VERSION 5.8 ;
BUSBITCHARS "[]" ;
DIVIDERCHAR "/" ;
UNITS
    DATABASE MICRONS 1000 ;
END UNITS

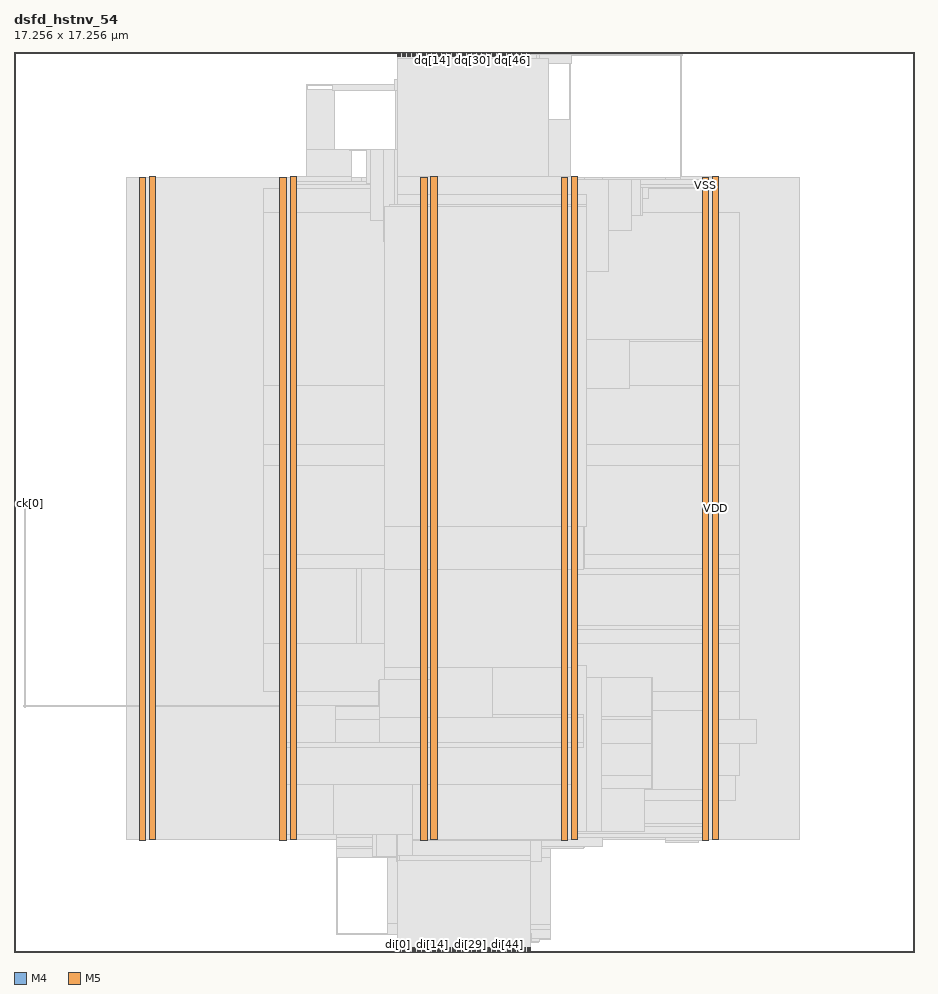
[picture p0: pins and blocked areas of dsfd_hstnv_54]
MACRO dsfd_hstnv_54
  FOREIGN dsfd_hstnv_54 0 0 ;
  CLASS BLOCK ;
  SIZE 17.256 BY 17.256 ;
  PIN ck[0]
    DIRECTION INPUT ;
    USE SIGNAL ;
    PORT
      LAYER M4 ;
        RECT  0 8.592 0.084 8.616 ;
    END
    PORT
      LAYER M4 ;
        RECT  0.06 8.592 0.227 8.616 ;
    END
  END ck[0]
  PIN di[0]
    DIRECTION INPUT ;
    USE SIGNAL ;
    PORT
      LAYER M5 ;
        RECT  7.344 0 7.368 0.084 ;
    END
  END di[0]
  PIN di[10]
    DIRECTION INPUT ;
    USE SIGNAL ;
    PORT
      LAYER M5 ;
        RECT  7.824 0 7.848 0.084 ;
    END
  END di[10]
  PIN di[11]
    DIRECTION INPUT ;
    USE SIGNAL ;
    PORT
      LAYER M5 ;
        RECT  7.872 0 7.896 0.084 ;
    END
  END di[11]
  PIN di[12]
    DIRECTION INPUT ;
    USE SIGNAL ;
    PORT
      LAYER M5 ;
        RECT  7.92 0 7.944 0.084 ;
    END
  END di[12]
  PIN di[13]
    DIRECTION INPUT ;
    USE SIGNAL ;
    PORT
      LAYER M5 ;
        RECT  7.968 0 7.992 0.084 ;
    END
  END di[13]
  PIN di[14]
    DIRECTION INPUT ;
    USE SIGNAL ;
    PORT
      LAYER M5 ;
        RECT  8.016 0 8.04 0.084 ;
    END
  END di[14]
  PIN di[15]
    DIRECTION INPUT ;
    USE SIGNAL ;
    PORT
      LAYER M5 ;
        RECT  8.064 0 8.088 0.084 ;
    END
  END di[15]
  PIN di[16]
    DIRECTION INPUT ;
    USE SIGNAL ;
    PORT
      LAYER M5 ;
        RECT  8.112 0 8.136 0.084 ;
    END
  END di[16]
  PIN di[17]
    DIRECTION INPUT ;
    USE SIGNAL ;
    PORT
      LAYER M5 ;
        RECT  8.16 0 8.184 0.084 ;
    END
  END di[17]
  PIN di[18]
    DIRECTION INPUT ;
    USE SIGNAL ;
    PORT
      LAYER M5 ;
        RECT  8.208 0 8.232 0.084 ;
    END
  END di[18]
  PIN di[19]
    DIRECTION INPUT ;
    USE SIGNAL ;
    PORT
      LAYER M5 ;
        RECT  8.256 0 8.28 0.084 ;
    END
  END di[19]
  PIN di[1]
    DIRECTION INPUT ;
    USE SIGNAL ;
    PORT
      LAYER M5 ;
        RECT  7.392 0 7.416 0.084 ;
    END
  END di[1]
  PIN di[20]
    DIRECTION INPUT ;
    USE SIGNAL ;
    PORT
      LAYER M5 ;
        RECT  8.304 0 8.328 0.084 ;
    END
  END di[20]
  PIN di[21]
    DIRECTION INPUT ;
    USE SIGNAL ;
    PORT
      LAYER M5 ;
        RECT  8.352 0 8.376 0.084 ;
    END
  END di[21]
  PIN di[22]
    DIRECTION INPUT ;
    USE SIGNAL ;
    PORT
      LAYER M5 ;
        RECT  8.4 0 8.424 0.084 ;
    END
  END di[22]
  PIN di[23]
    DIRECTION INPUT ;
    USE SIGNAL ;
    PORT
      LAYER M5 ;
        RECT  8.448 0 8.472 0.084 ;
    END
  END di[23]
  PIN di[24]
    DIRECTION INPUT ;
    USE SIGNAL ;
    PORT
      LAYER M5 ;
        RECT  8.496 0 8.52 0.084 ;
    END
  END di[24]
  PIN di[25]
    DIRECTION INPUT ;
    USE SIGNAL ;
    PORT
      LAYER M5 ;
        RECT  8.544 0 8.568 0.084 ;
    END
  END di[25]
  PIN di[26]
    DIRECTION INPUT ;
    USE SIGNAL ;
    PORT
      LAYER M5 ;
        RECT  8.592 0 8.616 0.084 ;
    END
  END di[26]
  PIN di[27]
    DIRECTION INPUT ;
    USE SIGNAL ;
    PORT
      LAYER M5 ;
        RECT  8.64 0 8.664 0.084 ;
    END
  END di[27]
  PIN di[28]
    DIRECTION INPUT ;
    USE SIGNAL ;
    PORT
      LAYER M5 ;
        RECT  8.688 0 8.712 0.084 ;
    END
  END di[28]
  PIN di[29]
    DIRECTION INPUT ;
    USE SIGNAL ;
    PORT
      LAYER M5 ;
        RECT  8.736 0 8.76 0.084 ;
    END
  END di[29]
  PIN di[2]
    DIRECTION INPUT ;
    USE SIGNAL ;
    PORT
      LAYER M5 ;
        RECT  7.44 0 7.464 0.084 ;
    END
  END di[2]
  PIN di[30]
    DIRECTION INPUT ;
    USE SIGNAL ;
    PORT
      LAYER M5 ;
        RECT  8.784 0 8.808 0.084 ;
    END
  END di[30]
  PIN di[31]
    DIRECTION INPUT ;
    USE SIGNAL ;
    PORT
      LAYER M5 ;
        RECT  8.832 0 8.856 0.084 ;
    END
  END di[31]
  PIN di[32]
    DIRECTION INPUT ;
    USE SIGNAL ;
    PORT
      LAYER M5 ;
        RECT  8.88 0 8.904 0.084 ;
    END
  END di[32]
  PIN di[33]
    DIRECTION INPUT ;
    USE SIGNAL ;
    PORT
      LAYER M5 ;
        RECT  8.928 0 8.952 0.084 ;
    END
  END di[33]
  PIN di[34]
    DIRECTION INPUT ;
    USE SIGNAL ;
    PORT
      LAYER M5 ;
        RECT  8.976 0 9 0.084 ;
    END
  END di[34]
  PIN di[35]
    DIRECTION INPUT ;
    USE SIGNAL ;
    PORT
      LAYER M5 ;
        RECT  9.024 0 9.048 0.084 ;
    END
  END di[35]
  PIN di[36]
    DIRECTION INPUT ;
    USE SIGNAL ;
    PORT
      LAYER M5 ;
        RECT  9.072 0 9.096 0.084 ;
    END
  END di[36]
  PIN di[37]
    DIRECTION INPUT ;
    USE SIGNAL ;
    PORT
      LAYER M5 ;
        RECT  9.12 0 9.144 0.084 ;
    END
  END di[37]
  PIN di[38]
    DIRECTION INPUT ;
    USE SIGNAL ;
    PORT
      LAYER M5 ;
        RECT  9.168 0 9.192 0.084 ;
    END
  END di[38]
  PIN di[39]
    DIRECTION INPUT ;
    USE SIGNAL ;
    PORT
      LAYER M5 ;
        RECT  9.216 0 9.24 0.084 ;
    END
  END di[39]
  PIN di[3]
    DIRECTION INPUT ;
    USE SIGNAL ;
    PORT
      LAYER M5 ;
        RECT  7.488 0 7.512 0.084 ;
    END
  END di[3]
  PIN di[40]
    DIRECTION INPUT ;
    USE SIGNAL ;
    PORT
      LAYER M5 ;
        RECT  9.264 0 9.288 0.084 ;
    END
  END di[40]
  PIN di[41]
    DIRECTION INPUT ;
    USE SIGNAL ;
    PORT
      LAYER M5 ;
        RECT  9.312 0 9.336 0.084 ;
    END
  END di[41]
  PIN di[42]
    DIRECTION INPUT ;
    USE SIGNAL ;
    PORT
      LAYER M5 ;
        RECT  9.36 0 9.384 0.084 ;
    END
  END di[42]
  PIN di[43]
    DIRECTION INPUT ;
    USE SIGNAL ;
    PORT
      LAYER M5 ;
        RECT  9.408 0 9.432 0.084 ;
    END
  END di[43]
  PIN di[44]
    DIRECTION INPUT ;
    USE SIGNAL ;
    PORT
      LAYER M5 ;
        RECT  9.456 0 9.48 0.084 ;
    END
  END di[44]
  PIN di[45]
    DIRECTION INPUT ;
    USE SIGNAL ;
    PORT
      LAYER M5 ;
        RECT  9.504 0 9.528 0.084 ;
    END
  END di[45]
  PIN di[46]
    DIRECTION INPUT ;
    USE SIGNAL ;
    PORT
      LAYER M5 ;
        RECT  9.552 0 9.576 0.084 ;
    END
  END di[46]
  PIN di[47]
    DIRECTION INPUT ;
    USE SIGNAL ;
    PORT
      LAYER M5 ;
        RECT  9.6 0 9.624 0.084 ;
    END
  END di[47]
  PIN di[48]
    DIRECTION INPUT ;
    USE SIGNAL ;
    PORT
      LAYER M5 ;
        RECT  9.648 0 9.672 0.084 ;
    END
  END di[48]
  PIN di[49]
    DIRECTION INPUT ;
    USE SIGNAL ;
    PORT
      LAYER M5 ;
        RECT  9.696 0 9.72 0.084 ;
    END
  END di[49]
  PIN di[4]
    DIRECTION INPUT ;
    USE SIGNAL ;
    PORT
      LAYER M5 ;
        RECT  7.536 0 7.56 0.084 ;
    END
  END di[4]
  PIN di[50]
    DIRECTION INPUT ;
    USE SIGNAL ;
    PORT
      LAYER M5 ;
        RECT  9.744 0 9.768 0.084 ;
    END
  END di[50]
  PIN di[51]
    DIRECTION INPUT ;
    USE SIGNAL ;
    PORT
      LAYER M5 ;
        RECT  9.792 0 9.816 0.084 ;
    END
  END di[51]
  PIN di[52]
    DIRECTION INPUT ;
    USE SIGNAL ;
    PORT
      LAYER M5 ;
        RECT  9.84 0 9.864 0.084 ;
    END
  END di[52]
  PIN di[53]
    DIRECTION INPUT ;
    USE SIGNAL ;
    PORT
      LAYER M5 ;
        RECT  9.888 0 9.912 0.084 ;
    END
  END di[53]
  PIN di[5]
    DIRECTION INPUT ;
    USE SIGNAL ;
    PORT
      LAYER M5 ;
        RECT  7.584 0 7.608 0.084 ;
    END
  END di[5]
  PIN di[6]
    DIRECTION INPUT ;
    USE SIGNAL ;
    PORT
      LAYER M5 ;
        RECT  7.632 0 7.656 0.084 ;
    END
  END di[6]
  PIN di[7]
    DIRECTION INPUT ;
    USE SIGNAL ;
    PORT
      LAYER M5 ;
        RECT  7.68 0 7.704 0.084 ;
    END
  END di[7]
  PIN di[8]
    DIRECTION INPUT ;
    USE SIGNAL ;
    PORT
      LAYER M5 ;
        RECT  7.728 0 7.752 0.084 ;
    END
  END di[8]
  PIN di[9]
    DIRECTION INPUT ;
    USE SIGNAL ;
    PORT
      LAYER M5 ;
        RECT  7.776 0 7.8 0.084 ;
    END
  END di[9]
  PIN dq[0]
    DIRECTION OUTPUT ;
    USE SIGNAL ;
    PORT
      LAYER M5 ;
        RECT  7.344 17.172 7.368 17.256 ;
    END
  END dq[0]
  PIN dq[10]
    DIRECTION OUTPUT ;
    USE SIGNAL ;
    PORT
      LAYER M5 ;
        RECT  7.824 17.172 7.848 17.256 ;
    END
  END dq[10]
  PIN dq[11]
    DIRECTION OUTPUT ;
    USE SIGNAL ;
    PORT
      LAYER M5 ;
        RECT  7.872 17.172 7.896 17.256 ;
    END
  END dq[11]
  PIN dq[12]
    DIRECTION OUTPUT ;
    USE SIGNAL ;
    PORT
      LAYER M5 ;
        RECT  7.92 17.172 7.944 17.256 ;
    END
  END dq[12]
  PIN dq[13]
    DIRECTION OUTPUT ;
    USE SIGNAL ;
    PORT
      LAYER M5 ;
        RECT  7.968 17.172 7.992 17.256 ;
    END
  END dq[13]
  PIN dq[14]
    DIRECTION OUTPUT ;
    USE SIGNAL ;
    PORT
      LAYER M5 ;
        RECT  8.016 17.172 8.04 17.256 ;
    END
  END dq[14]
  PIN dq[15]
    DIRECTION OUTPUT ;
    USE SIGNAL ;
    PORT
      LAYER M5 ;
        RECT  8.064 17.172 8.088 17.256 ;
    END
  END dq[15]
  PIN dq[16]
    DIRECTION OUTPUT ;
    USE SIGNAL ;
    PORT
      LAYER M5 ;
        RECT  8.112 17.172 8.136 17.256 ;
    END
  END dq[16]
  PIN dq[17]
    DIRECTION OUTPUT ;
    USE SIGNAL ;
    PORT
      LAYER M5 ;
        RECT  8.16 17.172 8.184 17.256 ;
    END
  END dq[17]
  PIN dq[18]
    DIRECTION OUTPUT ;
    USE SIGNAL ;
    PORT
      LAYER M5 ;
        RECT  8.208 17.172 8.232 17.256 ;
    END
  END dq[18]
  PIN dq[19]
    DIRECTION OUTPUT ;
    USE SIGNAL ;
    PORT
      LAYER M5 ;
        RECT  8.256 17.172 8.28 17.256 ;
    END
  END dq[19]
  PIN dq[1]
    DIRECTION OUTPUT ;
    USE SIGNAL ;
    PORT
      LAYER M5 ;
        RECT  7.392 17.172 7.416 17.256 ;
    END
  END dq[1]
  PIN dq[20]
    DIRECTION OUTPUT ;
    USE SIGNAL ;
    PORT
      LAYER M5 ;
        RECT  8.304 17.172 8.328 17.256 ;
    END
  END dq[20]
  PIN dq[21]
    DIRECTION OUTPUT ;
    USE SIGNAL ;
    PORT
      LAYER M5 ;
        RECT  8.352 17.172 8.376 17.256 ;
    END
  END dq[21]
  PIN dq[22]
    DIRECTION OUTPUT ;
    USE SIGNAL ;
    PORT
      LAYER M5 ;
        RECT  8.4 17.172 8.424 17.256 ;
    END
  END dq[22]
  PIN dq[23]
    DIRECTION OUTPUT ;
    USE SIGNAL ;
    PORT
      LAYER M5 ;
        RECT  8.448 17.172 8.472 17.256 ;
    END
  END dq[23]
  PIN dq[24]
    DIRECTION OUTPUT ;
    USE SIGNAL ;
    PORT
      LAYER M5 ;
        RECT  8.496 17.172 8.52 17.256 ;
    END
  END dq[24]
  PIN dq[25]
    DIRECTION OUTPUT ;
    USE SIGNAL ;
    PORT
      LAYER M5 ;
        RECT  8.544 17.172 8.568 17.256 ;
    END
  END dq[25]
  PIN dq[26]
    DIRECTION OUTPUT ;
    USE SIGNAL ;
    PORT
      LAYER M5 ;
        RECT  8.592 17.172 8.616 17.256 ;
    END
  END dq[26]
  PIN dq[27]
    DIRECTION OUTPUT ;
    USE SIGNAL ;
    PORT
      LAYER M5 ;
        RECT  8.64 17.172 8.664 17.256 ;
    END
  END dq[27]
  PIN dq[28]
    DIRECTION OUTPUT ;
    USE SIGNAL ;
    PORT
      LAYER M5 ;
        RECT  8.688 17.172 8.712 17.256 ;
    END
  END dq[28]
  PIN dq[29]
    DIRECTION OUTPUT ;
    USE SIGNAL ;
    PORT
      LAYER M5 ;
        RECT  8.736 17.172 8.76 17.256 ;
    END
  END dq[29]
  PIN dq[2]
    DIRECTION OUTPUT ;
    USE SIGNAL ;
    PORT
      LAYER M5 ;
        RECT  7.44 17.172 7.464 17.256 ;
    END
  END dq[2]
  PIN dq[30]
    DIRECTION OUTPUT ;
    USE SIGNAL ;
    PORT
      LAYER M5 ;
        RECT  8.784 17.172 8.808 17.256 ;
    END
  END dq[30]
  PIN dq[31]
    DIRECTION OUTPUT ;
    USE SIGNAL ;
    PORT
      LAYER M5 ;
        RECT  8.832 17.172 8.856 17.256 ;
    END
  END dq[31]
  PIN dq[32]
    DIRECTION OUTPUT ;
    USE SIGNAL ;
    PORT
      LAYER M5 ;
        RECT  8.88 17.172 8.904 17.256 ;
    END
  END dq[32]
  PIN dq[33]
    DIRECTION OUTPUT ;
    USE SIGNAL ;
    PORT
      LAYER M5 ;
        RECT  8.928 17.172 8.952 17.256 ;
    END
  END dq[33]
  PIN dq[34]
    DIRECTION OUTPUT ;
    USE SIGNAL ;
    PORT
      LAYER M5 ;
        RECT  8.976 17.172 9 17.256 ;
    END
  END dq[34]
  PIN dq[35]
    DIRECTION OUTPUT ;
    USE SIGNAL ;
    PORT
      LAYER M5 ;
        RECT  9.024 17.172 9.048 17.256 ;
    END
  END dq[35]
  PIN dq[36]
    DIRECTION OUTPUT ;
    USE SIGNAL ;
    PORT
      LAYER M5 ;
        RECT  9.072 17.172 9.096 17.256 ;
    END
  END dq[36]
  PIN dq[37]
    DIRECTION OUTPUT ;
    USE SIGNAL ;
    PORT
      LAYER M5 ;
        RECT  9.12 17.172 9.144 17.256 ;
    END
  END dq[37]
  PIN dq[38]
    DIRECTION OUTPUT ;
    USE SIGNAL ;
    PORT
      LAYER M5 ;
        RECT  9.168 17.172 9.192 17.256 ;
    END
  END dq[38]
  PIN dq[39]
    DIRECTION OUTPUT ;
    USE SIGNAL ;
    PORT
      LAYER M5 ;
        RECT  9.216 17.172 9.24 17.256 ;
    END
  END dq[39]
  PIN dq[3]
    DIRECTION OUTPUT ;
    USE SIGNAL ;
    PORT
      LAYER M5 ;
        RECT  7.488 17.172 7.512 17.256 ;
    END
  END dq[3]
  PIN dq[40]
    DIRECTION OUTPUT ;
    USE SIGNAL ;
    PORT
      LAYER M5 ;
        RECT  9.264 17.172 9.288 17.256 ;
    END
  END dq[40]
  PIN dq[41]
    DIRECTION OUTPUT ;
    USE SIGNAL ;
    PORT
      LAYER M5 ;
        RECT  9.312 17.172 9.336 17.256 ;
    END
  END dq[41]
  PIN dq[42]
    DIRECTION OUTPUT ;
    USE SIGNAL ;
    PORT
      LAYER M5 ;
        RECT  9.36 17.172 9.384 17.256 ;
    END
  END dq[42]
  PIN dq[43]
    DIRECTION OUTPUT ;
    USE SIGNAL ;
    PORT
      LAYER M5 ;
        RECT  9.408 17.172 9.432 17.256 ;
    END
  END dq[43]
  PIN dq[44]
    DIRECTION OUTPUT ;
    USE SIGNAL ;
    PORT
      LAYER M5 ;
        RECT  9.456 17.172 9.48 17.256 ;
    END
  END dq[44]
  PIN dq[45]
    DIRECTION OUTPUT ;
    USE SIGNAL ;
    PORT
      LAYER M5 ;
        RECT  9.504 17.172 9.528 17.256 ;
    END
  END dq[45]
  PIN dq[46]
    DIRECTION OUTPUT ;
    USE SIGNAL ;
    PORT
      LAYER M5 ;
        RECT  9.552 17.172 9.576 17.256 ;
    END
  END dq[46]
  PIN dq[47]
    DIRECTION OUTPUT ;
    USE SIGNAL ;
    PORT
      LAYER M5 ;
        RECT  9.6 17.172 9.624 17.256 ;
    END
  END dq[47]
  PIN dq[48]
    DIRECTION OUTPUT ;
    USE SIGNAL ;
    PORT
      LAYER M5 ;
        RECT  9.648 17.172 9.672 17.256 ;
    END
  END dq[48]
  PIN dq[49]
    DIRECTION OUTPUT ;
    USE SIGNAL ;
    PORT
      LAYER M5 ;
        RECT  9.696 17.172 9.72 17.256 ;
    END
  END dq[49]
  PIN dq[4]
    DIRECTION OUTPUT ;
    USE SIGNAL ;
    PORT
      LAYER M5 ;
        RECT  7.536 17.172 7.56 17.256 ;
    END
  END dq[4]
  PIN dq[50]
    DIRECTION OUTPUT ;
    USE SIGNAL ;
    PORT
      LAYER M5 ;
        RECT  9.744 17.172 9.768 17.256 ;
    END
  END dq[50]
  PIN dq[51]
    DIRECTION OUTPUT ;
    USE SIGNAL ;
    PORT
      LAYER M5 ;
        RECT  9.792 17.172 9.816 17.256 ;
    END
  END dq[51]
  PIN dq[52]
    DIRECTION OUTPUT ;
    USE SIGNAL ;
    PORT
      LAYER M5 ;
        RECT  9.84 17.172 9.864 17.256 ;
    END
  END dq[52]
  PIN dq[53]
    DIRECTION OUTPUT ;
    USE SIGNAL ;
    PORT
      LAYER M5 ;
        RECT  9.888 17.172 9.912 17.256 ;
    END
  END dq[53]
  PIN dq[5]
    DIRECTION OUTPUT ;
    USE SIGNAL ;
    PORT
      LAYER M5 ;
        RECT  7.584 17.172 7.608 17.256 ;
    END
  END dq[5]
  PIN dq[6]
    DIRECTION OUTPUT ;
    USE SIGNAL ;
    PORT
      LAYER M5 ;
        RECT  7.632 17.172 7.656 17.256 ;
    END
  END dq[6]
  PIN dq[7]
    DIRECTION OUTPUT ;
    USE SIGNAL ;
    PORT
      LAYER M5 ;
        RECT  7.68 17.172 7.704 17.256 ;
    END
  END dq[7]
  PIN dq[8]
    DIRECTION OUTPUT ;
    USE SIGNAL ;
    PORT
      LAYER M5 ;
        RECT  7.728 17.172 7.752 17.256 ;
    END
  END dq[8]
  PIN dq[9]
    DIRECTION OUTPUT ;
    USE SIGNAL ;
    PORT
      LAYER M5 ;
        RECT  7.776 17.172 7.8 17.256 ;
    END
  END dq[9]
  PIN VDD
    DIRECTION INOUT ;
    USE POWER ;
    PORT
      LAYER M5 ;
        RECT  13.392 2.151 13.512 14.873 ;
        RECT  10.692 2.151 10.812 14.873 ;
        RECT  7.992 2.151 8.112 14.873 ;
        RECT  5.292 2.151 5.412 14.873 ;
        RECT  2.592 2.151 2.712 14.873 ;
    END
  END VDD
  PIN VSS
    DIRECTION INOUT ;
    USE GROUND ;
    PORT
      LAYER M5 ;
        RECT  13.2 2.137 13.32 14.859 ;
        RECT  10.5 2.137 10.62 14.859 ;
        RECT  7.8 2.137 7.92 14.859 ;
        RECT  5.1 2.137 5.22 14.859 ;
        RECT  2.4 2.137 2.52 14.859 ;
    END
  END VSS
  # OT_OBS_CLOSED layer=M5 d_um=1.536 added=4
  OBS
    LAYER RVTN ;
     RECT  2.16 2.16 15.066 2.295 ;
     RECT  2.16 2.565 15.066 2.835 ;
     RECT  2.16 3.105 15.066 3.375 ;
     RECT  2.16 3.645 15.066 3.915 ;
     RECT  2.16 4.185 15.066 4.455 ;
     RECT  2.16 4.725 15.066 4.995 ;
     RECT  2.16 5.265 15.066 5.535 ;
     RECT  2.16 5.805 15.066 6.075 ;
     RECT  2.16 6.345 15.066 6.615 ;
     RECT  2.16 6.885 15.066 7.155 ;
     RECT  2.16 7.425 15.066 7.695 ;
     RECT  2.16 7.965 15.066 8.235 ;
     RECT  2.16 8.505 15.066 8.775 ;
     RECT  2.16 9.045 15.066 9.315 ;
     RECT  2.16 9.585 15.066 9.855 ;
     RECT  2.16 10.125 15.066 10.395 ;
     RECT  2.16 10.665 15.066 10.935 ;
     RECT  2.16 11.205 15.066 11.475 ;
     RECT  2.16 11.745 15.066 12.015 ;
     RECT  2.16 12.285 15.066 12.555 ;
     RECT  2.16 12.825 15.066 13.095 ;
     RECT  2.16 13.365 15.066 13.635 ;
     RECT  2.16 13.905 15.066 14.175 ;
     RECT  2.16 14.445 15.066 14.715 ;
    LAYER RVTP ;
     RECT  2.16 2.295 15.066 2.565 ;
     RECT  2.16 2.835 15.066 3.105 ;
     RECT  2.16 3.375 15.066 3.645 ;
     RECT  2.16 3.915 15.066 4.185 ;
     RECT  2.16 4.455 15.066 4.725 ;
     RECT  2.16 4.995 15.066 5.265 ;
     RECT  2.16 5.535 15.066 5.805 ;
     RECT  2.16 6.075 15.066 6.345 ;
     RECT  2.16 6.615 15.066 6.885 ;
     RECT  2.16 7.155 15.066 7.425 ;
     RECT  2.16 7.695 15.066 7.965 ;
     RECT  2.16 8.235 15.066 8.505 ;
     RECT  2.16 8.775 15.066 9.045 ;
     RECT  2.16 9.315 15.066 9.585 ;
     RECT  2.16 9.855 15.066 10.125 ;
     RECT  2.16 10.395 15.066 10.665 ;
     RECT  2.16 10.935 15.066 11.205 ;
     RECT  2.16 11.475 15.066 11.745 ;
     RECT  2.16 12.015 15.066 12.285 ;
     RECT  2.16 12.555 15.066 12.825 ;
     RECT  2.16 13.095 15.066 13.365 ;
     RECT  2.16 13.635 15.066 13.905 ;
     RECT  2.16 14.175 15.066 14.445 ;
     RECT  2.16 14.715 15.066 14.85 ;
    LAYER M1 ;
     RECT  2.16 2.151 15.066 14.859 ;
    LAYER M2 ;
     RECT  2.16 2.151 6.655 14.859 ;
     RECT  6.655 2.106 8.123 14.859 ;
     RECT  8.123 2.151 9.391 14.859 ;
     RECT  9.391 2.034 9.967 14.859 ;
     RECT  9.967 1.998 10.931 14.859 ;
     RECT  10.931 2.034 11.291 14.859 ;
     RECT  11.291 2.151 12.487 14.859 ;
     RECT  12.487 2.106 13.127 14.859 ;
     RECT  13.127 2.151 15.066 14.859 ;
    LAYER M3 ;
     RECT  8.856 0.091 8.874 0.187 ;
     RECT  9.864 0.139 9.882 0.187 ;
     RECT  7.668 0.187 8.874 0.235 ;
     RECT  9.864 0.187 10.062 0.235 ;
     RECT  7.668 0.235 10.278 0.427 ;
     RECT  7.524 0.427 10.278 0.523 ;
     RECT  6.192 0.331 6.21 1.819 ;
     RECT  7.164 0.523 10.278 1.819 ;
     RECT  6.192 1.819 10.278 1.993 ;
     RECT  6.192 1.993 10.926 2.029 ;
     RECT  12.492 2.101 13.122 2.143 ;
     RECT  6.192 2.029 11.286 2.191 ;
     RECT  12.492 2.143 13.305 2.191 ;
     RECT  6.192 2.191 13.305 2.263 ;
     RECT  2.415 2.143 2.505 2.413 ;
     RECT  5.115 2.143 5.205 2.413 ;
     RECT  6.192 2.263 13.374 2.413 ;
     RECT  5.115 2.413 5.397 2.461 ;
     RECT  6.192 2.413 13.497 2.461 ;
     RECT  5.115 2.461 13.497 2.911 ;
     RECT  5.115 2.911 13.842 3.379 ;
     RECT  5.115 3.379 13.914 3.991 ;
     RECT  5.115 3.991 14.238 4.451 ;
     RECT  5.115 4.451 13.914 4.999 ;
     RECT  4.788 4.999 13.914 5.909 ;
     RECT  7.308 5.909 13.914 6.179 ;
     RECT  7.38 6.179 13.914 6.269 ;
     RECT  7.56 6.269 13.914 7.231 ;
     RECT  4.788 5.909 6.57 7.357 ;
     RECT  7.38 7.231 13.914 7.357 ;
     RECT  4.788 7.357 13.914 7.619 ;
     RECT  4.788 7.619 8.097 9.319 ;
     RECT  8.82 7.619 13.914 9.319 ;
     RECT  4.788 9.319 13.914 9.725 ;
     RECT  4.788 9.725 9.09 10.867 ;
     RECT  10.368 9.725 13.914 10.867 ;
     RECT  4.788 10.867 13.914 14.171 ;
     RECT  2.415 2.413 2.697 14.597 ;
     RECT  4.788 14.171 13.497 14.639 ;
     RECT  5.307 14.639 9.198 14.711 ;
     RECT  10.224 14.639 13.497 14.717 ;
     RECT  5.307 14.711 9.126 14.765 ;
     RECT  7.236 14.765 9.126 14.813 ;
     RECT  11.988 14.717 13.497 14.813 ;
     RECT  10.224 14.717 11.178 14.819 ;
     RECT  12.348 14.813 13.497 14.819 ;
     RECT  7.308 14.813 9.126 14.861 ;
     RECT  2.607 14.597 2.697 14.867 ;
     RECT  5.307 14.765 6.462 14.867 ;
     RECT  10.224 14.819 10.797 14.867 ;
     RECT  12.78 14.819 13.497 14.867 ;
     RECT  5.616 14.867 6.462 15.389 ;
     RECT  10.224 14.867 10.674 15.965 ;
     RECT  5.616 15.389 6.138 16.541 ;
     RECT  5.616 16.541 5.634 16.637 ;
     RECT  7.308 14.861 9.054 16.733 ;
     RECT  7.776 16.733 9.054 17.035 ;
     RECT  7.776 17.035 9.198 17.069 ;
     RECT  10.656 15.965 10.674 17.069 ;
     RECT  7.776 17.069 7.794 17.117 ;
     RECT  9.18 17.069 9.198 17.213 ;
     RECT  12.78 14.867 12.798 17.213 ;
    LAYER M4 ;
     RECT  0.181 4.704 2.408 4.728 ;
     RECT  2.408 2.148 2.512 14.592 ;
     RECT  2.512 2.418 2.6 14.592 ;
     RECT  2.6 2.418 2.704 14.862 ;
     RECT  2.704 4.704 5.108 4.728 ;
     RECT  5.108 2.148 5.212 14.592 ;
     RECT  5.212 2.256 5.3 14.592 ;
     RECT  5.3 2.256 5.404 14.862 ;
     RECT  5.605 16.608 6.109 16.632 ;
     RECT  5.404 3.984 6.157 4.728 ;
     RECT  6.433 15.36 6.757 15.384 ;
     RECT  6.757 14.736 6.829 15.384 ;
     RECT  5.404 2.256 6.865 2.28 ;
     RECT  6.865 1.824 6.956 2.28 ;
     RECT  6.157 4.704 6.997 4.728 ;
     RECT  6.829 14.016 7.081 15.384 ;
     RECT  6.181 0.336 7.153 0.36 ;
     RECT  6.997 4.704 7.189 5.208 ;
     RECT  7.081 13.632 7.297 15.384 ;
     RECT  6.109 16.512 7.297 16.632 ;
     RECT  6.956 1.824 7.325 3.24 ;
     RECT  7.325 1.728 7.381 3.24 ;
     RECT  7.189 4.704 7.381 5.88 ;
     RECT  7.153 0.336 7.405 0.552 ;
     RECT  7.381 1.728 7.405 6.264 ;
     RECT  7.297 13.536 7.405 15.384 ;
     RECT  7.405 13.488 7.429 15.384 ;
     RECT  7.405 0.336 7.489 6.264 ;
     RECT  7.489 0.336 7.657 0.6 ;
     RECT  7.489 1.728 7.669 6.264 ;
     RECT  7.429 13.152 7.669 15.384 ;
     RECT  7.297 16.512 7.717 16.728 ;
     RECT  7.657 0.192 7.763 0.6 ;
     RECT  7.717 16.512 7.805 17.112 ;
     RECT  7.669 1.728 7.808 6.696 ;
     RECT  7.669 13.104 7.808 15.384 ;
     RECT  7.808 1.728 7.955 15.384 ;
     RECT  7.805 16.512 8.081 17.064 ;
     RECT  7.955 1.728 8.104 14.862 ;
     RECT  8.104 1.728 8.273 1.8 ;
     RECT  8.104 2.784 8.345 6.888 ;
     RECT  8.345 2.88 8.435 6.888 ;
     RECT  7.763 0.192 8.485 0.552 ;
     RECT  8.485 0.096 8.675 0.552 ;
     RECT  8.435 2.976 8.705 6.888 ;
     RECT  8.081 15.936 8.821 17.064 ;
     RECT  8.675 0.096 8.885 0.36 ;
     RECT  8.104 9.072 8.915 9.096 ;
     RECT  8.104 11.04 9.137 14.856 ;
     RECT  8.821 15.936 9.169 17.112 ;
     RECT  8.273 1.728 9.377 1.752 ;
     RECT  8.705 2.976 9.445 6.84 ;
     RECT  9.377 1.728 9.521 1.8 ;
     RECT  9.521 1.728 9.877 1.848 ;
     RECT  9.445 2.88 9.877 6.84 ;
     RECT  9.877 1.728 9.889 6.84 ;
     RECT  8.885 0.144 9.893 0.36 ;
     RECT  9.893 0.192 9.929 0.36 ;
     RECT  9.169 15.936 10.019 17.208 ;
     RECT  10.019 16.992 10.067 17.208 ;
     RECT  9.929 0.192 10.073 0.264 ;
     RECT  9.889 1.728 10.109 7.416 ;
     RECT  10.019 15.936 10.253 15.96 ;
     RECT  10.073 0.24 10.289 0.264 ;
     RECT  10.109 2.148 10.508 7.416 ;
     RECT  9.349 8.496 10.508 8.52 ;
     RECT  9.637 9.696 10.508 9.72 ;
     RECT  9.137 11.04 10.508 14.808 ;
     RECT  10.508 2.148 10.612 14.808 ;
     RECT  10.067 17.04 10.685 17.208 ;
     RECT  10.612 2.304 10.7 14.808 ;
     RECT  10.7 2.304 10.804 14.862 ;
     RECT  10.804 7.344 10.931 8.184 ;
     RECT  10.804 2.304 10.973 5.496 ;
     RECT  10.931 8.16 10.979 8.184 ;
     RECT  10.973 2.304 11.261 5.256 ;
     RECT  10.804 13.056 11.405 14.808 ;
     RECT  10.804 10.8 11.801 11.736 ;
     RECT  11.405 13.824 11.837 14.808 ;
     RECT  11.837 14.112 12.017 14.808 ;
     RECT  12.017 14.112 12.053 14.664 ;
     RECT  11.261 2.304 12.089 3.144 ;
     RECT  12.053 14.448 12.161 14.664 ;
     RECT  12.089 3.12 12.229 3.144 ;
     RECT  11.261 4.512 12.229 5.256 ;
     RECT  12.229 3.12 12.233 5.256 ;
     RECT  10.685 17.184 12.809 17.208 ;
     RECT  12.233 3.12 13.208 4.632 ;
     RECT  11.801 11.712 13.208 11.736 ;
     RECT  12.161 14.64 13.208 14.664 ;
     RECT  13.208 2.148 13.312 14.664 ;
     RECT  13.312 2.418 13.4 14.664 ;
     RECT  13.4 2.418 13.504 14.862 ;
    LAYER M5 ;
     RECT  7.344 0.016 9.912 1.763 ;
     RECT  7.392 1.763 9.912 1.859 ;
     RECT  7.632 1.859 9.912 2.137 ;
     RECT  2.4 2.137 2.52 2.151 ;
     RECT  5.1 2.137 5.22 2.151 ;
     RECT  7.632 2.137 10.62 2.151 ;
     RECT  13.2 2.137 13.32 2.151 ;
     RECT  5.1 2.151 5.412 2.245 ;
     RECT  5.1 2.245 6.12 3.205 ;
     RECT  7.632 2.151 10.812 3.205 ;
     RECT  5.1 3.205 10.812 3.925 ;
     RECT  5.1 3.925 10.92 4.019 ;
     RECT  7.008 4.019 10.92 4.499 ;
     RECT  9.168 4.499 10.92 4.547 ;
     RECT  7.008 4.499 8.112 5.219 ;
     RECT  7.104 5.219 8.112 5.461 ;
     RECT  9.168 4.547 10.812 5.461 ;
     RECT  7.104 5.461 10.812 7.333 ;
     RECT  7.104 7.333 10.92 8.149 ;
     RECT  0.192 4.693 0.216 8.627 ;
     RECT  7.104 8.149 10.968 14.291 ;
     RECT  7.2 14.291 10.968 14.339 ;
     RECT  7.344 14.339 10.968 14.531 ;
     RECT  2.4 2.151 2.712 14.859 ;
     RECT  5.1 4.019 5.412 14.859 ;
     RECT  13.2 2.151 13.512 14.859 ;
     RECT  2.592 14.859 2.712 14.873 ;
     RECT  5.292 14.859 5.412 14.873 ;
     RECT  7.344 14.531 10.812 14.873 ;
     RECT  13.392 14.859 13.512 14.873 ;
     RECT  7.344 14.873 10.248 17.123 ;
     RECT  7.344 17.123 9.912 17.232 ;
     RECT  7.344 1.763 7.392 1.859 ;
     RECT  7.344 1.859 7.632 2.245 ;
     RECT  6.12 2.245 7.632 3.205 ;
     RECT  8.112 4.499 9.168 5.461 ;
  END
END dsfd_hstnv_54
END LIBRARY
